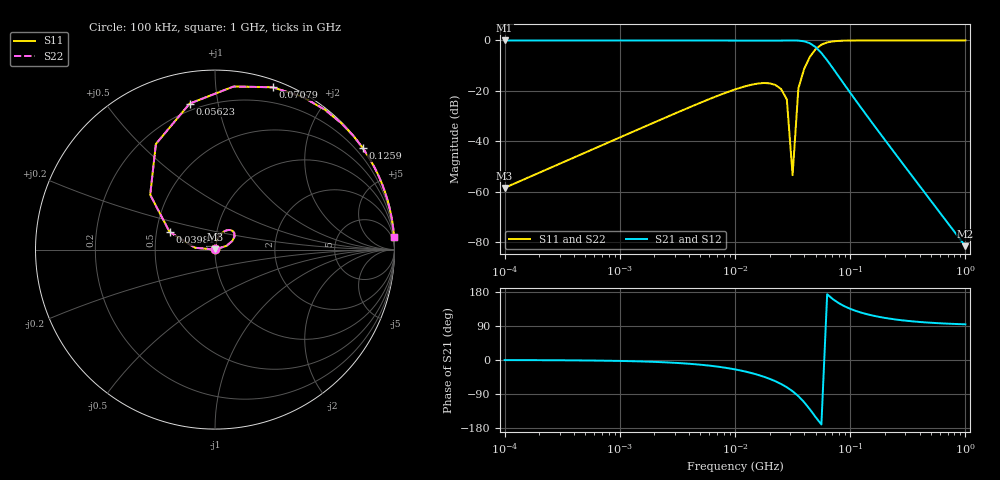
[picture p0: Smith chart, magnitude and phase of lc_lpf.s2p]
# Hz S RI R 50
! golden: lc_lpf
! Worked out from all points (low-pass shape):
!   81 points, 100 kHz to 1 GHz, reference 50 ohm
!   highest |S21| = 0.00 dB at 100 kHz (marker M1); lowest = -81.6 dB at 1 GHz (marker M2)
!   |S21| within 3 dB of the highest: start of sweep to 51.08 MHz
!   lowest |S11| = -58.5 dB at 100 kHz (marker M3), VSWR 1.00, Z = 50 + j0.119 ohm
!   |S11| at or under -10 dB: start of sweep to 41.14 MHz
!   |S22| runs from -58.5 to 0.0 dB; largest |S21 - S12| = 0
!   S11 on the Smith chart (normalised r, x): 100 kHz: 1.00, +0.00; 39.81 MHz: 0.59, +0.12; 56.23 MHz: 0.16, +0.83; 70.79 MHz: 0.06, +1.41; 125.9 MHz: 0.01, +3.21; 1 GHz: 0, +28
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100000  5.18e-06 0.00119  1 -0.00434  1 -0.00434  5.18e-06 0.00119
501187.2  0.00013 0.00598  0.9997 -0.0217  0.9997 -0.0217  0.00013 0.00598
2238721  0.00258 0.0265  0.9949 -0.0969  0.9949 -0.0969  0.00258 0.0265
5011872  0.0125 0.0569  0.9749 -0.215  0.9749 -0.215  0.0125 0.0569
1e7  0.0447 0.0969  0.9027 -0.4167  0.9027 -0.4167  0.0447 0.0969
1.778279e7  0.0998 0.1029  0.7105 -0.689  0.7105 -0.689  0.0998 0.1029
2.238721e7  0.1089 0.0736  0.555 -0.8214  0.555 -0.8214  0.1089 0.0736
2.511886e7  0.0973 0.0489  0.4466 -0.8881  0.4466 -0.8881  0.0973 0.0489
2.818383e7  0.0642 0.0209  0.3087 -0.9488  0.3087 -0.9488  0.0642 0.0209
3.162278e7  -0.00212 -0.000281  0.1315 -0.9913  0.1315 -0.9913  -0.00212 -0.000281
3.548134e7  -0.1115 0.0104  -0.0922 -0.9894  -0.0922 -0.9894  -0.1115 0.0104
3.981072e7  -0.2532 0.0984  -0.3487 -0.897  -0.3487 -0.897  -0.2532 0.0984
4.466836e7  -0.3611 0.3054  -0.569 -0.6727  -0.569 -0.6727  -0.3611 0.3054
5.011872e7  -0.3294 0.5884  -0.6444 -0.3607  -0.6444 -0.3607  -0.3294 0.5884
5.623413e7  -0.1412 0.8135  -0.5558 -0.0964  -0.5558 -0.0964  -0.1412 0.8135
6.309573e7  0.1036 0.9088  -0.4017 0.0458  -0.4017 0.0458  0.1036 0.9088
7.079458e7  0.3211 0.9044  -0.2649 0.094  -0.2649 0.094  0.3211 0.9044
8.912509e7  0.6124 0.7793  -0.1048 0.0824  -0.1048 0.0824  0.6124 0.7793
1.258925e8  0.8222 0.5674  -0.0253 0.0366  -0.0253 0.0366  0.8222 0.5674
2.238721e8  0.9467 0.3221  -0.00244 0.00717  -0.00244 0.00717  0.9467 0.3221
8.912509e8  0.9967 0.0812  -9.56e-06 0.000117  -9.56e-06 0.000117  0.9967 0.0812
1e9  0.9974 0.0723  -6.03e-06 8.32e-05  -6.03e-06 8.32e-05  0.9974 0.0723
